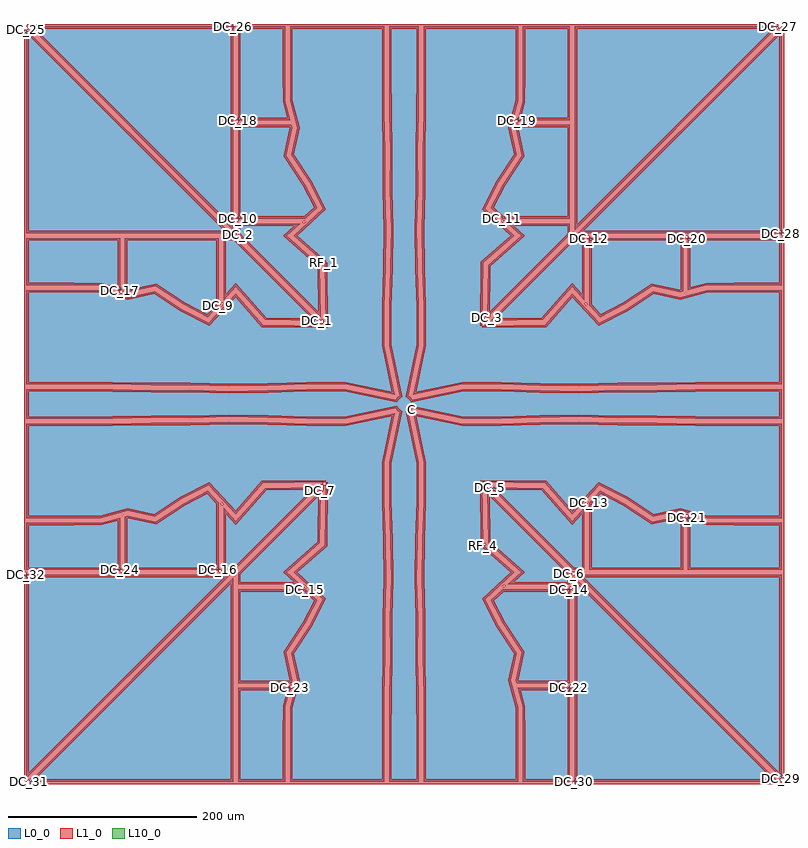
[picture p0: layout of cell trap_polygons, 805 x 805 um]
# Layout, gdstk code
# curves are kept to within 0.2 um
import gdstk
lib = gdstk.Library(unit=1e-6, precision=1e-09)
def P(c, l, *ps):  # polygons
    for p in ps: c.add(gdstk.Polygon(p, *l))
L0_0 = (0, 0)
L1_0 = (1, 0)
L10_0 = (10, 0)

trap_polygons = lib.new_cell('trap_polygons')
P(trap_polygons, L0_0, [(-400,-180.75),(-184.286,-180.75),(-400,-396.464),(-400,-180.75)],
  [(-396.464,-400),(-180.75,-184.286),(-180.75,-400),(-396.464,-400)],
  [(180.75,-400),(180.75,-184.286),(396.464,-400),(180.75,-400)],
  [(400,-396.464),(184.286,-180.75),(400,-180.75),(400,-396.464)],
  [(400,180.75),(184.286,180.75),(400,396.464),(400,180.75)],
  [(396.464,400),(180.75,184.286),(180.75,400),(396.464,400)],
  [(-180.75,400),(-180.75,184.286),(-396.464,400),(-180.75,400)],
  [(-400,396.464),(-184.286,180.75),(-400,180.75),(-400,396.464)],
  [(-300.579,-175.75),(-320.279,-175.75),(-349.567,-175.75),(-400,-175.75),(-400,-125.75),(-349.567,-125.75),(-320.279,-125.64),(-300.579,-120.481),(-300.579,-175.75)],
  [(-120.481,-300.579),(-125.64,-320.279),(-125.75,-349.567),(-125.75,-400),(-175.75,-400),(-175.75,-349.567),(-175.75,-320.279),(-175.75,-300.579),(-120.481,-300.579)],
  [(175.75,-300.579),(175.75,-320.279),(175.75,-349.567),(175.75,-400),(125.75,-400),(125.75,-349.567),(125.64,-320.279),(120.481,-300.579),(175.75,-300.579)],
  [(300.579,-120.481),(320.279,-125.64),(349.567,-125.75),(400,-125.75),(400,-175.75),(349.567,-175.75),(320.279,-175.75),(300.579,-175.75),(300.579,-120.481)],
  [(300.579,175.75),(320.279,175.75),(349.567,175.75),(400,175.75),(400,125.75),(349.567,125.75),(320.279,125.64),(300.579,120.481),(300.579,175.75)],
  [(120.481,300.579),(125.64,320.279),(125.75,349.567),(125.75,400),(175.75,400),(175.75,349.567),(175.75,320.279),(175.75,300.579),(120.481,300.579)],
  [(-175.75,300.579),(-175.75,320.279),(-175.75,349.567),(-175.75,400),(-125.75,400),(-125.75,349.567),(-125.64,320.279),(-120.481,300.579),(-175.75,300.579)],
  [(-300.579,120.481),(-320.279,125.64),(-349.567,125.75),(-400,125.75),(-400,175.75),(-349.567,175.75),(-320.279,175.75),(-300.579,175.75),(-300.579,120.481)],
  [(-196.159,-175.75),(-295.579,-175.75),(-295.579,-119.172),(-292.572,-118.384),(-263.035,-124.717),(-232.858,-104.912),(-207.802,-92.104),(-196.159,-104.586)],
  [(-104.586,-196.159),(-92.104,-207.802),(-104.912,-232.858),(-124.717,-263.035),(-118.384,-292.572),(-119.172,-295.579),(-175.75,-295.579),(-175.75,-196.159)],
  [(175.75,-196.159),(175.75,-295.579),(119.172,-295.579),(118.384,-292.572),(124.717,-263.035),(104.912,-232.858),(92.104,-207.802),(104.586,-196.159)],
  [(196.159,-104.586),(207.802,-92.104),(232.858,-104.912),(263.035,-124.717),(292.572,-118.384),(295.579,-119.172),(295.579,-175.75),(196.159,-175.75)],
  [(196.159,175.75),(295.579,175.75),(295.579,119.172),(292.572,118.384),(263.035,124.717),(232.858,104.912),(207.802,92.104),(196.159,104.586)],
  [(104.586,196.159),(92.104,207.802),(104.912,232.858),(124.717,263.035),(118.384,292.572),(119.172,295.579),(175.75,295.579),(175.75,196.159)],
  [(-175.75,196.159),(-175.75,295.579),(-119.172,295.579),(-118.384,292.572),(-124.717,263.035),(-104.912,232.858),(-92.104,207.802),(-104.586,196.159)],
  [(-196.159,104.586),(-207.802,92.104),(-232.858,104.912),(-263.035,124.717),(-292.572,118.384),(-295.579,119.172),(-295.579,175.75),(-196.159,175.75)],
  [(-179.286,-175.75),(-191.159,-175.75),(-191.159,-109.946),(-177.951,-124.103),(-147.115,-89.006),(-91.738,-88.202),(-179.286,-175.75)],
  [(-88.202,-91.738),(-89.006,-147.115),(-124.103,-177.951),(-109.946,-191.159),(-175.75,-191.159),(-175.75,-179.286),(-88.202,-91.738)],
  [(175.75,-179.286),(175.75,-191.159),(109.946,-191.159),(124.103,-177.951),(89.006,-147.115),(88.202,-91.738),(175.75,-179.286)],
  [(91.738,-88.202),(147.115,-89.006),(177.951,-124.103),(191.159,-109.946),(191.159,-175.75),(179.286,-175.75),(91.738,-88.202)],
  [(179.286,175.75),(191.159,175.75),(191.159,109.946),(177.951,124.103),(147.115,89.006),(91.738,88.202),(179.286,175.75)],
  [(88.202,91.738),(89.006,147.115),(124.103,177.951),(109.946,191.159),(175.75,191.159),(175.75,179.286),(88.202,91.738)],
  [(-175.75,179.286),(-175.75,191.159),(-109.946,191.159),(-124.103,177.951),(-89.006,147.115),(-88.202,91.738),(-175.75,179.286)],
  [(-91.738,88.202),(-147.115,89.006),(-177.951,124.103),(-191.159,109.946),(-191.159,175.75),(-179.286,175.75),(-91.738,88.202)],
  [(8.315,-5.556),(6.344,-7.73),(4.67,-8.84),(15.75,-62.418),(15.75,-102.98),(14.386,-144.098),(13.755,-185.411),(14.97,-226.593),(14.772,-267.734),(15.728,-308.6),(15.75,-400),(-15.75,-400),(-15.728,-308.6),(-14.772,-267.734),(-14.97,-226.593),(-13.755,-185.411),(-14.386,-144.098),(-15.75,-102.98),(-15.75,-62.418),(-4.67,-8.84),(-7.071,-7.071),(-8.84,-4.67),(-62.418,-15.75),(-102.98,-15.75),(-144.098,-14.386),(-185.411,-13.755),(-226.593,-14.97),(-267.734,-14.772),(-308.6,-15.728),(-400,-15.75),(-400,15.75),(-308.6,15.728),(-267.734,14.772),(-226.593,14.97),(-185.411,13.755),(-144.098,14.386),(-102.98,15.75),(-62.418,15.75),(-8.84,4.67),(-7.071,7.071),(-4.67,8.84),(-15.75,62.418),(-15.75,102.98),(-14.386,144.098),(-13.755,185.411),(-14.97,226.593),(-14.772,267.734),(-15.728,308.6),(-15.75,400),(15.75,400),(15.728,308.6),(14.772,267.734),(14.97,226.593),(13.755,185.411),(14.386,144.098),(15.75,102.98),(15.75,62.418),(4.67,8.84),(7.071,7.071),(8.84,4.67),(62.418,15.75),(102.98,15.75),(144.098,14.386),(185.411,13.755),(226.593,14.97),(267.734,14.772),(308.6,15.728),(400,15.75),(400,-15.75),(308.6,-15.728),(267.734,-14.772),(226.593,-14.97),(185.411,-13.755),(144.098,-14.386),(102.98,-15.75),(62.418,-15.75),(8.84,-4.67)],
  [(84.038,-149.406),(116.654,-178.062),(85.935,-206.719),(100.583,-235.375),(119.39,-264.031),(113.246,-292.687),(120.75,-321.344),(120.75,-400),(20.75,-400),(20.736,-308.844),(19.772,-267.687),(19.97,-226.531),(18.756,-185.375),(19.384,-144.219),(20.75,-103.062),(20.75,-61.906),(10.02,-10.02),(61.906,-20.75),(103.062,-20.75),(144.219,-19.384),(185.375,-18.756),(226.531,-19.97),(267.687,-19.772),(308.844,-20.736),(400,-20.75),(400,-120.75),(321.344,-120.75),(292.687,-113.246),(264.031,-119.39),(235.375,-100.583),(206.719,-85.935),(178.062,-116.654),(149.406,-84.038),(83.076,-83.076)],
  [(83.076,83.076),(149.406,84.038),(178.062,116.654),(206.719,85.935),(235.375,100.583),(264.031,119.39),(292.687,113.246),(321.344,120.75),(400,120.75),(400,20.75),(308.844,20.736),(267.687,19.772),(226.531,19.97),(185.375,18.756),(144.219,19.384),(103.062,20.75),(61.906,20.75),(10.02,10.02),(20.75,61.906),(20.75,103.062),(19.384,144.219),(18.756,185.375),(19.97,226.531),(19.772,267.687),(20.736,308.844),(20.75,400),(120.75,400),(120.75,321.344),(113.246,292.687),(119.39,264.031),(100.583,235.375),(85.935,206.719),(116.654,178.062),(84.038,149.406)],
  [(-83.076,-83.076),(-149.406,-84.038),(-178.062,-116.654),(-206.719,-85.935),(-235.375,-100.583),(-264.031,-119.39),(-292.687,-113.246),(-321.344,-120.75),(-400,-120.75),(-400,-20.75),(-308.844,-20.736),(-267.687,-19.772),(-226.531,-19.97),(-185.375,-18.756),(-144.219,-19.384),(-103.062,-20.75),(-61.906,-20.75),(-10.02,-10.02),(-20.75,-61.906),(-20.75,-103.062),(-19.384,-144.219),(-18.756,-185.375),(-19.97,-226.531),(-19.772,-267.687),(-20.736,-308.844),(-20.75,-400),(-120.75,-400),(-120.75,-321.344),(-113.246,-292.687),(-119.39,-264.031),(-100.583,-235.375),(-85.935,-206.719),(-116.654,-178.062),(-84.038,-149.406)],
  [(-84.038,149.406),(-116.654,178.062),(-85.935,206.719),(-100.583,235.375),(-119.39,264.031),(-113.246,292.687),(-120.75,321.344),(-120.75,400),(-20.75,400),(-20.736,308.844),(-19.772,267.687),(-19.97,226.531),(-18.756,185.375),(-19.384,144.219),(-20.75,103.062),(-20.75,61.906),(-10.02,10.02),(-61.906,20.75),(-103.062,20.75),(-144.219,19.384),(-185.375,18.756),(-226.531,19.97),(-267.687,19.772),(-308.844,20.736),(-400,20.75),(-400,120.75),(-321.344,120.75),(-292.687,113.246),(-264.031,119.39),(-235.375,100.583),(-206.719,85.935),(-178.062,116.654),(-149.406,84.038),(-83.076,83.076)])
P(trap_polygons, L1_0, [(-400,-178.25),(-400,-183.25),(-190.321,-183.25),(-397.5,-390.429),(-397.5,-180.75),(-402.5,-180.75),(-402.5,-398.964),(-400,-400),(-180.75,-180.75),(-181.786,-178.25)],
  [(-398.232,-398.232),(-394.697,-401.768),(-183.25,-190.321),(-183.25,-397.5),(-396.464,-397.5),(-396.464,-402.5),(-178.25,-402.5),(-178.25,-181.786),(-180.75,-180.75)],
  [(178.25,-400),(183.25,-400),(183.25,-190.321),(390.429,-397.5),(180.75,-397.5),(180.75,-402.5),(398.964,-402.5),(400,-400),(180.75,-180.75),(178.25,-181.786)],
  [(398.232,-398.232),(401.768,-394.697),(190.321,-183.25),(397.5,-183.25),(397.5,-396.464),(402.5,-396.464),(402.5,-178.25),(181.786,-178.25),(180.75,-180.75)],
  [(400,178.25),(400,183.25),(190.321,183.25),(397.5,390.429),(397.5,180.75),(402.5,180.75),(402.5,398.964),(400,400),(180.75,180.75),(181.786,178.25)],
  [(398.232,398.232),(394.697,401.768),(183.25,190.321),(183.25,397.5),(396.464,397.5),(396.464,402.5),(178.25,402.5),(178.25,181.786),(180.75,180.75)],
  [(-178.25,400),(-183.25,400),(-183.25,190.321),(-390.429,397.5),(-180.75,397.5),(-180.75,402.5),(-398.964,402.5),(-400,400),(-180.75,180.75),(-178.25,181.786)],
  [(-398.232,398.232),(-401.768,394.697),(-190.321,183.25),(-397.5,183.25),(-397.5,396.464),(-402.5,396.464),(-402.5,178.25),(-181.786,178.25),(-180.75,180.75)],
  [(-300.579,-178.25),(-300.579,-173.25),(-397.5,-173.25),(-397.5,-128.25),(-319.952,-128.139),(-303.079,-123.72),(-303.079,-175.75),(-298.079,-175.75),(-298.079,-117.981),(-298.794,-117.429),(-320.605,-123.141),(-402.5,-123.25),(-402.5,-178.25)],
  [(-118.063,-301.213),(-122.9,-299.946),(-128.139,-319.952),(-128.25,-397.5),(-173.25,-397.5),(-173.25,-303.079),(-120.481,-303.079),(-120.481,-298.079),(-178.25,-298.079),(-178.25,-402.5),(-123.25,-402.5),(-123.141,-320.605)],
  [(178.25,-300.579),(173.25,-300.579),(173.25,-397.5),(128.25,-397.5),(128.139,-319.952),(123.72,-303.079),(175.75,-303.079),(175.75,-298.079),(117.981,-298.079),(117.429,-298.794),(123.141,-320.605),(123.25,-402.5),(178.25,-402.5)],
  [(301.213,-118.063),(299.946,-122.9),(319.952,-128.139),(397.5,-128.25),(397.5,-173.25),(303.079,-173.25),(303.079,-120.481),(298.079,-120.481),(298.079,-178.25),(402.5,-178.25),(402.5,-123.25),(320.605,-123.141)],
  [(300.579,178.25),(300.579,173.25),(397.5,173.25),(397.5,128.25),(319.952,128.139),(303.079,123.72),(303.079,175.75),(298.079,175.75),(298.079,117.981),(298.794,117.429),(320.605,123.141),(402.5,123.25),(402.5,178.25)],
  [(118.063,301.213),(122.9,299.946),(128.139,319.952),(128.25,397.5),(173.25,397.5),(173.25,303.079),(120.481,303.079),(120.481,298.079),(178.25,298.079),(178.25,402.5),(123.25,402.5),(123.141,320.605)],
  [(-178.25,300.579),(-173.25,300.579),(-173.25,397.5),(-128.25,397.5),(-128.139,319.952),(-123.72,303.079),(-175.75,303.079),(-175.75,298.079),(-117.981,298.079),(-117.429,298.794),(-123.141,320.605),(-123.25,402.5),(-178.25,402.5)],
  [(-301.213,118.063),(-299.946,122.9),(-319.952,128.139),(-397.5,128.25),(-397.5,173.25),(-303.079,173.25),(-303.079,120.481),(-298.079,120.481),(-298.079,178.25),(-402.5,178.25),(-402.5,123.25),(-320.605,123.141)],
  [(-196.159,-178.25),(-196.159,-173.25),(-293.079,-173.25),(-293.079,-121.102),(-292.514,-120.954),(-262.538,-127.38),(-231.6,-107.077),(-208.343,-95.189),(-198.659,-105.571),(-198.659,-175.75),(-193.659,-175.75),(-193.659,-103.601),(-207.26,-89.02),(-234.117,-102.748),(-263.533,-122.053),(-292.63,-115.815),(-298.079,-117.242),(-298.079,-178.25)],
  [(-102.88,-194.33),(-106.291,-197.987),(-95.189,-208.343),(-107.077,-231.6),(-127.38,-262.538),(-120.954,-292.514),(-121.102,-293.079),(-173.25,-293.079),(-173.25,-198.659),(-104.586,-198.659),(-104.586,-193.659),(-178.25,-193.659),(-178.25,-298.079),(-117.242,-298.079),(-115.815,-292.63),(-122.053,-263.533),(-102.748,-234.117),(-89.02,-207.26)],
  [(178.25,-196.159),(173.25,-196.159),(173.25,-293.079),(121.102,-293.079),(120.954,-292.514),(127.38,-262.538),(107.077,-231.6),(95.189,-208.343),(105.571,-198.659),(175.75,-198.659),(175.75,-193.659),(103.601,-193.659),(89.02,-207.26),(102.748,-234.117),(122.053,-263.533),(115.815,-292.63),(117.242,-298.079),(178.25,-298.079)],
  [(194.33,-102.88),(197.987,-106.291),(208.343,-95.189),(231.6,-107.077),(262.538,-127.38),(292.514,-120.954),(293.079,-121.102),(293.079,-173.25),(198.659,-173.25),(198.659,-104.586),(193.659,-104.586),(193.659,-178.25),(298.079,-178.25),(298.079,-117.242),(292.63,-115.815),(263.533,-122.053),(234.117,-102.748),(207.26,-89.02)],
  [(196.159,178.25),(196.159,173.25),(293.079,173.25),(293.079,121.102),(292.514,120.954),(262.538,127.38),(231.6,107.077),(208.343,95.189),(198.659,105.571),(198.659,175.75),(193.659,175.75),(193.659,103.601),(207.26,89.02),(234.117,102.748),(263.533,122.053),(292.63,115.815),(298.079,117.242),(298.079,178.25)],
  [(102.88,194.33),(106.291,197.987),(95.189,208.343),(107.077,231.6),(127.38,262.538),(120.954,292.514),(121.102,293.079),(173.25,293.079),(173.25,198.659),(104.586,198.659),(104.586,193.659),(178.25,193.659),(178.25,298.079),(117.242,298.079),(115.815,292.63),(122.053,263.533),(102.748,234.117),(89.02,207.26)],
  [(-178.25,196.159),(-173.25,196.159),(-173.25,293.079),(-121.102,293.079),(-120.954,292.514),(-127.38,262.538),(-107.077,231.6),(-95.189,208.343),(-105.571,198.659),(-175.75,198.659),(-175.75,193.659),(-103.601,193.659),(-89.02,207.26),(-102.748,234.117),(-122.053,263.533),(-115.815,292.63),(-117.242,298.079),(-178.25,298.079)],
  [(-194.33,102.88),(-197.987,106.291),(-208.343,95.189),(-231.6,107.077),(-262.538,127.38),(-292.514,120.954),(-293.079,121.102),(-293.079,173.25),(-198.659,173.25),(-198.659,104.586),(-193.659,104.586),(-193.659,178.25),(-298.079,178.25),(-298.079,117.242),(-292.63,115.815),(-263.533,122.053),(-234.117,102.748),(-207.26,89.02)],
  [(-179.286,-178.25),(-179.286,-173.25),(-188.659,-173.25),(-188.659,-116.29),(-178.074,-127.637),(-177.723,-127.632),(-145.969,-91.489),(-97.862,-90.791),(-181.053,-173.982),(-177.518,-177.518),(-88.202,-88.202),(-89.274,-85.666),(-148.261,-86.522),(-178.007,-120.379),(-191.036,-106.412),(-193.659,-107.446),(-193.659,-178.25)],
  [(-85.703,-91.774),(-90.702,-91.702),(-91.489,-145.969),(-127.632,-177.723),(-127.637,-178.074),(-116.29,-188.659),(-173.25,-188.659),(-173.25,-180.321),(-86.435,-93.506),(-89.97,-89.97),(-178.25,-178.25),(-178.25,-193.659),(-107.446,-193.659),(-106.412,-191.036),(-120.379,-178.007),(-86.522,-148.261)],
  [(178.25,-179.286),(173.25,-179.286),(173.25,-188.659),(116.29,-188.659),(127.637,-178.074),(127.632,-177.723),(91.489,-145.969),(90.791,-97.862),(173.982,-181.053),(177.518,-177.518),(88.202,-88.202),(85.666,-89.274),(86.522,-148.261),(120.379,-178.007),(106.412,-191.036),(107.446,-193.659),(178.25,-193.659)],
  [(91.774,-85.703),(91.702,-90.702),(145.969,-91.489),(177.723,-127.632),(178.074,-127.637),(188.659,-116.29),(188.659,-173.25),(180.321,-173.25),(93.506,-86.435),(89.97,-89.97),(178.25,-178.25),(193.659,-178.25),(193.659,-107.446),(191.036,-106.412),(178.007,-120.379),(148.261,-86.522)],
  [(179.286,178.25),(179.286,173.25),(188.659,173.25),(188.659,116.29),(178.074,127.637),(177.723,127.632),(145.969,91.489),(97.862,90.791),(181.053,173.982),(177.518,177.518),(88.202,88.202),(89.274,85.666),(148.261,86.522),(178.007,120.379),(191.036,106.412),(193.659,107.446),(193.659,178.25)],
  [(85.703,91.774),(90.702,91.702),(91.489,145.969),(127.632,177.723),(127.637,178.074),(116.29,188.659),(173.25,188.659),(173.25,180.321),(86.435,93.506),(89.97,89.97),(178.25,178.25),(178.25,193.659),(107.446,193.659),(106.412,191.036),(120.379,178.007),(86.522,148.261)],
  [(-178.25,179.286),(-173.25,179.286),(-173.25,188.659),(-116.29,188.659),(-127.637,178.074),(-127.632,177.723),(-91.489,145.969),(-90.791,97.862),(-173.982,181.053),(-177.518,177.518),(-88.202,88.202),(-85.666,89.274),(-86.522,148.261),(-120.379,178.007),(-106.412,191.036),(-107.446,193.659),(-178.25,193.659)],
  [(-91.774,85.703),(-91.702,90.702),(-145.969,91.489),(-177.723,127.632),(-178.074,127.637),(-188.659,116.29),(-188.659,173.25),(-180.321,173.25),(-93.506,86.435),(-89.97,89.97),(-178.25,178.25),(-193.659,178.25),(-193.659,107.446),(-191.036,106.412),(-178.007,120.379),(-148.261,86.522)],
  [(18.25,-349.999),(18.228,-308.57),(17.272,-267.711),(17.47,-226.562),(16.256,-185.393),(16.885,-144.158),(18.25,-103.021),(18.25,-62.162),(7.517,-10.259),(5.894,-11.027),(7.932,-9.665),(10.323,-7.045),(8.317,-5.557),(10.459,-6.841),(11.027,-5.894),(10.259,-7.517),(62.162,-18.25),(103.021,-18.25),(144.158,-16.885),(185.393,-16.256),(226.562,-17.47),(267.711,-17.272),(308.57,-18.228),(402.5,-18.25),(402.5,-1.824),(397.5,-1.824),(397.5,-13.25),(308.63,-13.228),(267.757,-12.272),(226.624,-12.47),(185.428,-11.254),(144.037,-11.886),(102.938,-13.25),(62.674,-13.25),(7.42,-1.824),(6.231,-4.168),(5.301,-5.301),(4.165,-6.234),(1.824,-7.42),(13.25,-62.674),(13.25,-102.938),(11.886,-144.037),(11.254,-185.428),(12.47,-226.624),(12.272,-267.757),(13.228,-308.63),(13.25,-397.5),(-13.25,-397.5),(-13.228,-308.63),(-12.272,-267.757),(-12.47,-226.624),(-11.254,-185.428),(-11.886,-144.037),(-13.25,-102.938),(-13.25,-62.674),(-1.824,-7.42),(-4.165,-6.234),(-5.301,-5.301),(-6.234,-4.165),(-7.42,-1.824),(-62.674,-13.25),(-102.938,-13.25),(-144.037,-11.886),(-185.428,-11.254),(-226.624,-12.47),(-267.757,-12.272),(-308.63,-13.228),(-397.5,-13.25),(-397.5,-1.824),(-402.5,-1.824),(-402.5,-18.25),(-308.57,-18.228),(-267.711,-17.272),(-226.562,-17.47),(-185.393,-16.256),(-144.158,-16.885),(-103.021,-18.25),(-62.162,-18.25),(-10.259,-7.517),(-11.027,-5.894),(-8.841,-8.841),(-5.894,-11.027),(-7.517,-10.259),(-18.25,-62.162),(-18.25,-103.021),(-16.885,-144.158),(-16.256,-185.393),(-17.47,-226.562),(-17.272,-267.711),(-18.228,-308.57),(-18.25,-402.5),(18.25,-402.5)],
  [(402.5,18.25),(308.57,18.228),(267.711,17.272),(226.562,17.47),(185.393,16.256),(144.158,16.885),(103.021,18.25),(62.162,18.25),(10.259,7.517),(11.027,5.894),(8.841,8.841),(5.894,11.027),(7.517,10.259),(18.25,62.162),(18.25,103.021),(16.885,144.158),(16.256,185.393),(17.47,226.562),(17.272,267.711),(18.228,308.57),(18.25,402.5),(-18.25,402.5),(-18.228,308.57),(-17.272,267.711),(-17.47,226.562),(-16.256,185.393),(-16.885,144.158),(-18.25,103.021),(-18.25,62.162),(-7.517,10.259),(-5.894,11.027),(-8.841,8.841),(-11.027,5.894),(-10.259,7.517),(-62.162,18.25),(-103.021,18.25),(-144.158,16.885),(-185.393,16.256),(-226.562,17.47),(-267.711,17.272),(-308.57,18.228),(-402.5,18.25),(-402.5,-1.824),(-397.5,-1.824),(-397.5,13.25),(-308.63,13.228),(-267.757,12.272),(-226.624,12.47),(-185.428,11.254),(-144.037,11.886),(-102.938,13.25),(-62.674,13.25),(-7.42,1.824),(-6.234,4.165),(-5.301,5.301),(-4.165,6.234),(-1.824,7.42),(-13.25,62.674),(-13.25,102.938),(-11.886,144.037),(-11.254,185.428),(-12.47,226.624),(-12.272,267.757),(-13.228,308.63),(-13.25,397.5),(13.25,397.5),(13.228,308.63),(12.272,267.757),(12.47,226.624),(11.254,185.428),(11.886,144.037),(13.25,102.938),(13.25,62.674),(1.824,7.42),(4.165,6.234),(5.301,5.301),(6.234,4.165),(7.42,1.824),(62.674,13.25),(102.938,13.25),(144.037,11.886),(185.428,11.254),(226.624,12.47),(267.757,12.272),(308.63,13.228),(397.5,13.25),(397.5,-1.824),(402.5,-1.824)],
  [(85.688,-147.528),(82.388,-151.284),(112.93,-178.118),(82.851,-206.177),(98.419,-236.633),(116.726,-264.529),(110.677,-292.745),(118.25,-321.666),(118.25,-397.5),(23.25,-397.5),(23.235,-308.814),(22.272,-267.664),(22.47,-226.5),(21.257,-185.357),(21.884,-144.279),(23.25,-103.104),(23.25,-61.65),(13.239,-13.239),(61.65,-23.25),(103.104,-23.25),(144.279,-21.884),(185.357,-21.257),(226.5,-22.47),(267.664,-22.272),(308.814,-23.235),(397.5,-23.25),(397.5,-118.25),(321.666,-118.25),(292.745,-110.677),(264.529,-116.726),(236.633,-98.419),(206.177,-82.851),(178.118,-112.93),(150.552,-81.555),(80.613,-80.54),(81.538,-149.443),(86.538,-149.37),(85.613,-85.613),(148.261,-86.522),(177.834,-120.183),(178.185,-120.188),(207.26,-89.02),(234.117,-102.748),(263.533,-122.053),(292.63,-115.815),(321.022,-123.25),(402.5,-123.25),(402.5,-18.25),(308.873,-18.236),(267.711,-17.272),(226.562,-17.47),(185.393,-16.256),(144.158,-16.885),(103.021,-18.25),(62.162,-18.25),(8.079,-7.066),(7.066,-8.079),(18.25,-62.162),(18.25,-103.021),(16.885,-144.158),(16.256,-185.393),(17.47,-226.562),(17.272,-267.711),(18.236,-308.873),(18.25,-402.5),(123.25,-402.5),(123.25,-321.022),(115.815,-292.63),(122.053,-263.533),(102.748,-234.117),(89.02,-207.26),(120.188,-178.185),(120.183,-177.834)],
  [(83.04,85.576),(83.112,80.576),(150.552,81.555),(178.118,112.93),(206.177,82.851),(236.633,98.419),(264.529,116.726),(292.745,110.677),(321.666,118.25),(397.5,118.25),(397.5,23.25),(308.814,23.235),(267.664,22.272),(226.5,22.47),(185.357,21.257),(144.279,21.884),(103.104,23.25),(61.65,23.25),(13.239,13.239),(23.25,61.65),(23.25,103.104),(21.884,144.279),(21.257,185.357),(22.47,226.5),(22.272,267.664),(23.235,308.814),(23.25,397.5),(118.25,397.5),(118.25,321.666),(110.677,292.745),(116.726,264.529),(98.419,236.633),(82.851,206.177),(112.93,178.118),(81.555,150.552),(80.576,83.112),(85.576,83.04),(86.522,148.261),(120.183,177.834),(120.188,178.185),(89.02,207.26),(102.748,234.117),(122.053,263.533),(115.815,292.63),(123.25,321.022),(123.25,402.5),(18.25,402.5),(18.236,308.873),(17.272,267.711),(17.47,226.562),(16.256,185.393),(16.885,144.158),(18.25,103.021),(18.25,62.162),(7.066,8.079),(8.079,7.066),(62.162,18.25),(103.021,18.25),(144.158,16.885),(185.393,16.256),(226.562,17.47),(267.711,17.272),(308.873,18.236),(402.5,18.25),(402.5,123.25),(321.022,123.25),(292.63,115.815),(263.533,122.053),(234.117,102.748),(207.26,89.02),(178.185,120.188),(177.834,120.183),(148.261,86.522)],
  [(-83.04,-85.576),(-83.112,-80.576),(-150.552,-81.555),(-178.118,-112.93),(-206.177,-82.851),(-236.633,-98.419),(-264.529,-116.726),(-292.745,-110.677),(-321.666,-118.25),(-397.5,-118.25),(-397.5,-23.25),(-308.814,-23.235),(-267.664,-22.272),(-226.5,-22.47),(-185.357,-21.257),(-144.279,-21.884),(-103.104,-23.25),(-61.65,-23.25),(-13.239,-13.239),(-23.25,-61.65),(-23.25,-103.104),(-21.884,-144.279),(-21.257,-185.357),(-22.47,-226.5),(-22.272,-267.664),(-23.235,-308.814),(-23.25,-397.5),(-118.25,-397.5),(-118.25,-321.666),(-110.677,-292.745),(-116.726,-264.529),(-98.419,-236.633),(-82.851,-206.177),(-112.93,-178.118),(-81.555,-150.552),(-80.576,-83.112),(-85.576,-83.04),(-86.522,-148.261),(-120.183,-177.834),(-120.188,-178.185),(-89.02,-207.26),(-102.748,-234.117),(-122.053,-263.533),(-115.815,-292.63),(-123.25,-321.022),(-123.25,-402.5),(-18.25,-402.5),(-18.236,-308.873),(-17.272,-267.711),(-17.47,-226.562),(-16.256,-185.393),(-16.885,-144.158),(-18.25,-103.021),(-18.25,-62.162),(-7.066,-8.079),(-8.079,-7.066),(-62.162,-18.25),(-103.021,-18.25),(-144.158,-16.885),(-185.393,-16.256),(-226.562,-17.47),(-267.711,-17.272),(-308.873,-18.236),(-402.5,-18.25),(-402.5,-123.25),(-321.022,-123.25),(-292.63,-115.815),(-263.533,-122.053),(-234.117,-102.748),(-207.26,-89.02),(-178.185,-120.188),(-177.834,-120.183),(-148.261,-86.522)],
  [(-85.688,147.528),(-82.388,151.284),(-112.93,178.118),(-82.851,206.177),(-98.419,236.633),(-116.726,264.529),(-110.677,292.745),(-118.25,321.666),(-118.25,397.5),(-23.25,397.5),(-23.235,308.814),(-22.272,267.664),(-22.47,226.5),(-21.257,185.357),(-21.884,144.279),(-23.25,103.104),(-23.25,61.65),(-13.239,13.239),(-61.65,23.25),(-103.104,23.25),(-144.279,21.884),(-185.357,21.257),(-226.5,22.47),(-267.664,22.272),(-308.814,23.235),(-397.5,23.25),(-397.5,118.25),(-321.666,118.25),(-292.745,110.677),(-264.529,116.726),(-236.633,98.419),(-206.177,82.851),(-178.118,112.93),(-150.552,81.555),(-80.613,80.54),(-81.538,149.443),(-86.538,149.37),(-85.613,85.613),(-148.261,86.522),(-177.834,120.183),(-178.185,120.188),(-207.26,89.02),(-234.117,102.748),(-263.533,122.053),(-292.63,115.815),(-321.022,123.25),(-402.5,123.25),(-402.5,18.25),(-308.873,18.236),(-267.711,17.272),(-226.562,17.47),(-185.393,16.256),(-144.158,16.885),(-103.021,18.25),(-62.162,18.25),(-8.079,7.066),(-7.066,8.079),(-18.25,62.162),(-18.25,103.021),(-16.885,144.158),(-16.256,185.393),(-17.47,226.562),(-17.272,267.711),(-18.236,308.873),(-18.25,402.5),(-123.25,402.5),(-123.25,321.022),(-115.815,292.63),(-122.053,263.533),(-102.748,234.117),(-89.02,207.26),(-120.188,178.185),(-120.183,177.834)])
P(trap_polygons, L10_0, [(0,0),(0,0),(0,0),(0,0)])
trap_polygons.add(gdstk.Label('DC_32', (-400,-180.75), layer=2, texttype=0))
trap_polygons.add(gdstk.Label('DC_31', (-396.464,-400), layer=2, texttype=0))
trap_polygons.add(gdstk.Label('DC_30', (180.75,-400), layer=2, texttype=0))
trap_polygons.add(gdstk.Label('DC_29', (400,-396.464), layer=2, texttype=0))
trap_polygons.add(gdstk.Label('DC_28', (400,180.75), layer=2, texttype=0))
trap_polygons.add(gdstk.Label('DC_27', (396.464,400), layer=2, texttype=0))
trap_polygons.add(gdstk.Label('DC_26', (-180.75,400), layer=2, texttype=0))
trap_polygons.add(gdstk.Label('DC_25', (-400,396.464), layer=2, texttype=0))
trap_polygons.add(gdstk.Label('DC_24', (-300.579,-175.75), layer=2, texttype=0))
trap_polygons.add(gdstk.Label('DC_23', (-120.481,-300.579), layer=2, texttype=0))
trap_polygons.add(gdstk.Label('DC_22', (175.75,-300.579), layer=2, texttype=0))
trap_polygons.add(gdstk.Label('DC_21', (300.579,-120.481), layer=2, texttype=0))
trap_polygons.add(gdstk.Label('DC_20', (300.579,175.75), layer=2, texttype=0))
trap_polygons.add(gdstk.Label('DC_19', (120.481,300.579), layer=2, texttype=0))
trap_polygons.add(gdstk.Label('DC_18', (-175.75,300.579), layer=2, texttype=0))
trap_polygons.add(gdstk.Label('DC_17', (-300.579,120.481), layer=2, texttype=0))
trap_polygons.add(gdstk.Label('DC_16', (-196.159,-175.75), layer=2, texttype=0))
trap_polygons.add(gdstk.Label('DC_15', (-104.586,-196.159), layer=2, texttype=0))
trap_polygons.add(gdstk.Label('DC_14', (175.75,-196.159), layer=2, texttype=0))
trap_polygons.add(gdstk.Label('DC_13', (196.159,-104.586), layer=2, texttype=0))
trap_polygons.add(gdstk.Label('DC_12', (196.159,175.75), layer=2, texttype=0))
trap_polygons.add(gdstk.Label('DC_11', (104.586,196.159), layer=2, texttype=0))
trap_polygons.add(gdstk.Label('DC_10', (-175.75,196.159), layer=2, texttype=0))
trap_polygons.add(gdstk.Label('DC_9', (-196.159,104.586), layer=2, texttype=0))
trap_polygons.add(gdstk.Label('DC_8', (-179.286,-175.75), layer=2, texttype=0))
trap_polygons.add(gdstk.Label('DC_7', (-88.202,-91.738), layer=2, texttype=0))
trap_polygons.add(gdstk.Label('DC_6', (175.75,-179.286), layer=2, texttype=0))
trap_polygons.add(gdstk.Label('DC_5', (91.738,-88.202), layer=2, texttype=0))
trap_polygons.add(gdstk.Label('DC_4', (179.286,175.75), layer=2, texttype=0))
trap_polygons.add(gdstk.Label('DC_3', (88.202,91.738), layer=2, texttype=0))
trap_polygons.add(gdstk.Label('DC_2', (-175.75,179.286), layer=2, texttype=0))
trap_polygons.add(gdstk.Label('DC_1', (-91.738,88.202), layer=2, texttype=0))
trap_polygons.add(gdstk.Label('C', (8.315,-5.556), layer=2, texttype=0))
trap_polygons.add(gdstk.Label('RF_4', (84.038,-149.406), layer=2, texttype=0))
trap_polygons.add(gdstk.Label('RF_3', (83.076,83.076), layer=2, texttype=0))
trap_polygons.add(gdstk.Label('RF_2', (-83.076,-83.076), layer=2, texttype=0))
trap_polygons.add(gdstk.Label('RF_1', (-84.038,149.406), layer=2, texttype=0))

lib.write_gds('trap_polygons.gds')
